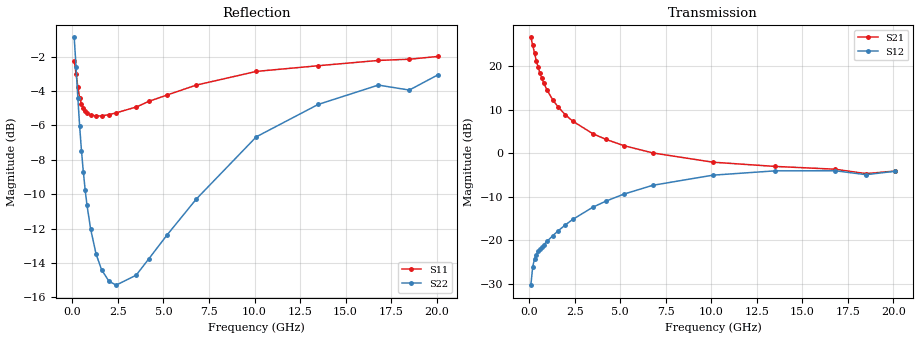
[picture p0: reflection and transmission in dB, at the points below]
!  Infineon Technologies AG
! BFR380L3 , PF131585-7, No.6, Th 09.10.01, soldered on pcb-board, measured with PP GSG850
!  Vce=1.5 V,  Ic=7.5 mA
! Common Emitter S-Parameters:  15. November 2001
#  GHz  S  MA  R  50
! f  S11  S21  S12  S22
! GHz  Mag  Ang  Mag  Ang  Mag  Ang  Mag  Ang
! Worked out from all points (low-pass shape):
!   201 points, 100 MHz to 20.1 GHz, reference 50 ohm
!   highest |S21| = 26.66 dB at 100 MHz (marker M1); lowest = -4.7 dB at 18.5 GHz (marker M2)
!   |S21| within 3 dB of the highest: start of sweep to 266.4 MHz
!   lowest |S11| = -5.4 dB at 1.6 GHz (marker M3), VSWR 3.29, Z = 15.2 + j0.428 ohm
!   |S11| at or under -10 dB: nowhere
!   |S22| runs from -15.3 to -0.9 dB; largest |S21 - S12| = 22
!   S11 on the Smith chart (normalised r, x): 100 MHz: 0.98, -2.42; 300 MHz: 0.37, -0.83; 1 GHz: 0.31, -0.15; 4.2 GHz: 0.30, +0.40; 10.1 GHz: 0.40, +1.16; 20.1 GHz: 0.95, +2.57
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0.1  0.7742 -39.7  21.53 154.7  0.03035 70.9  0.9045 -25.8
0.2  0.7098 -72.3  17.59 135.7  0.04925 57.3  0.7441 -45.3
0.3  0.648 -95.8  14.17 122.8  0.06104 50.2  0.6027 -58.5
0.4  0.6025 -113.1  11.62 113.8  0.06826 46.3  0.4978 -67.9
0.5  0.5798 -125.8  9.748 107.1  0.07402 45.1  0.4228 -75.0
0.6  0.5629 -135.7  8.351 102.0  0.07909 44.9  0.3679 -80.5
0.7  0.5516 -143.8  7.302 97.7  0.0835 45.2  0.3263 -85.2
0.8  0.5454 -150.4  6.47 94.1  0.08817 45.8  0.2946 -89.3
1  0.5379 -160.7  5.271 88.2  0.09744 47.4  0.2507 -96.1
1.3  0.5344 -172.2  4.124 80.9  0.1122 49.6  0.2119 -104.8
1.6  0.5341 178.9  3.395 74.7  0.1281 51.3  0.1907 -112.3
2  0.5388 169.1  2.76 67.5  0.1501 52.5  0.1767 -121.3
2.4  0.5454 161.2  2.339 60.9  0.1732 52.8  0.1719 -129.5
3.5  0.567 142.8  1.678 45.2  0.239 50.7  0.1837 -148.4
4.2  0.5891 133.1  1.45 36.6  0.2797 48.0  0.2051 -160.8
5.2  0.6147 120.9  1.223 25.7  0.3382 42.2  0.2406 -174.4
6.8  0.6569 103.4  1.007 11.4  0.4278 32.7  0.3059 162.6
10.1  0.72 77.5  0.7882 -8.6  0.5592 11.2  0.4645 127.7
13.5  0.7481 59.9  0.705 -23.2  0.6267 -9.9  0.5772 98.5
16.8  0.775 47.6  0.6549 -34.5  0.6291 -26.0  0.657 76.8
18.5  0.7814 45.5  0.5825 -41.6  0.5663 -34.5  0.6354 71.2
20.1  0.7963 38.3  0.6235 -44.8  0.6203 -39.5  0.705 60.5
